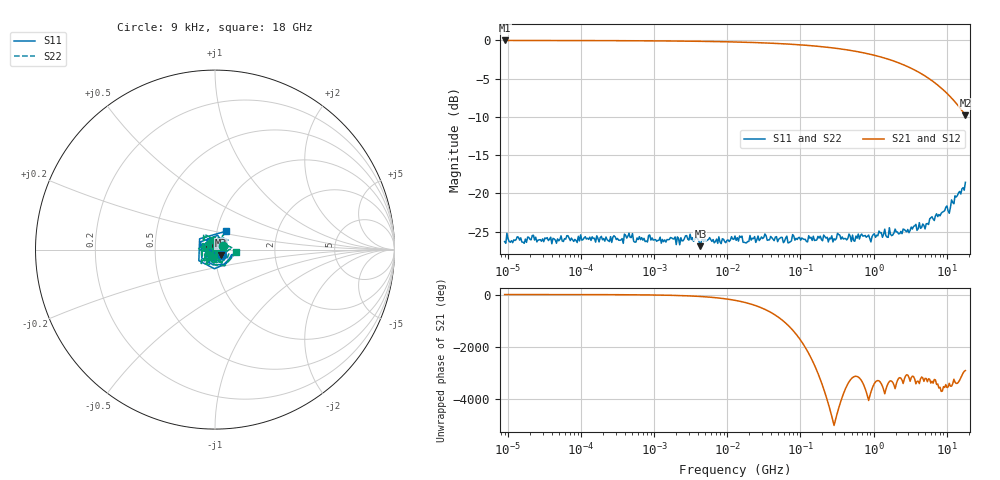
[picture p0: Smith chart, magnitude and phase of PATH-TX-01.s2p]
! CAL-ELEKTRA — DATOS SINTÉTICOS DE EJEMPLO: no son una medida real.
! Cable simulado PATH-TX-01: 12.0 m, 9 kHz – 18 GHz
# HZ S RI R 50
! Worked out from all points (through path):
!   401 points, 9 kHz to 18 GHz, reference 50 ohm
!   highest |S21| = -0.01 dB at 9 kHz (marker M1); lowest = -9.8 dB at 18 GHz (marker M2)
!   lowest |S11| = -26.9 dB at 4.287 MHz (marker M3), VSWR 1.09, Z = 53.3 - j3.29 ohm
!   |S11| at or under -10 dB: start of sweep to end of sweep
!   |S22| runs from -26.9 to -18.6 dB; largest |S21 - S12| = 0
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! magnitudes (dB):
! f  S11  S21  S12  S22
! 9 kHz  -26.3  0.0  0.0  -26.3
! 102.3 kHz  -26.1  0.0  0.0  -26.1
! 292.7 kHz  -25.7  0.0  0.0  -25.7
! 351 kHz  -26.1  0.0  0.0  -26.1
! 420.7 kHz  -25.8  0.0  0.0  -25.8
! 562.4 kHz  -26.4  0.0  0.0  -26.4
! 901.2 kHz  -26.1  -0.1  -0.1  -26.1
! 1.162 MHz  -26.1  -0.1  -0.1  -26.1
! 2.4 MHz  -26.2  -0.1  -0.1  -26.2
! 2.877 MHz  -26.0  -0.1  -0.1  -26.0
! 4.287 MHz  -26.9  -0.1  -0.1  -26.9
! 13.2 MHz  -26.2  -0.2  -0.2  -26.2
! 17.64 MHz  -26.5  -0.2  -0.2  -26.5
! 31.52 MHz  -25.8  -0.3  -0.3  -25.8
! 70 MHz  -26.4  -0.5  -0.5  -26.4
! 144.6 MHz  -26.2  -0.7  -0.7  -26.2
! 345.3 MHz  -25.5  -1.1  -1.1  -25.5
! 533.7 MHz  -26.2  -1.4  -1.4  -26.2
! 1.643 GHz  -24.5  -2.5  -2.5  -24.5
! 5.244 GHz  -24.0  -4.8  -4.8  -24.0
! 11.23 GHz  -21.9  -7.4  -7.4  -21.9
! 18 GHz  -18.6  -9.8  -9.8  -18.6
